VERSION 5.7 ;
  NOWIREEXTENSIONATPIN ON ;
  DIVIDERCHAR "/" ;
  BUSBITCHARS "[]" ;
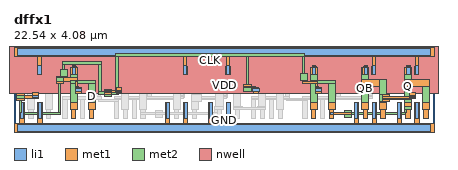
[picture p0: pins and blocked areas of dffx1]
MACRO dffx1
  CLASS BLOCK ;
  FOREIGN dffx1 ;
  ORIGIN 0.000 0.000 ;
  SIZE 22.540 BY 4.080 ;
  PIN CLK
    ANTENNAGATEAREA 1.323000 ;
    PORT
      LAYER li1 ;
        RECT 3.285 1.940 3.615 2.130 ;
        RECT 5.460 1.940 5.790 2.130 ;
        RECT 12.820 1.940 13.150 2.130 ;
        RECT 16.165 1.940 16.495 2.130 ;
        RECT 0.985 1.660 1.315 1.850 ;
      LAYER met1 ;
        RECT 2.470 2.780 2.850 3.130 ;
        RECT 2.260 2.730 2.850 2.780 ;
        RECT 2.260 2.520 3.430 2.730 ;
        RECT 15.350 2.540 15.730 2.920 ;
        RECT 2.260 2.400 2.640 2.520 ;
        RECT 3.290 2.240 3.430 2.520 ;
        RECT 15.470 2.520 15.730 2.540 ;
        RECT 15.470 2.380 16.310 2.520 ;
        RECT 12.340 2.240 12.720 2.360 ;
        RECT 16.170 2.240 16.310 2.380 ;
        RECT 3.290 2.200 3.440 2.240 ;
        RECT 12.340 2.200 12.950 2.240 ;
        RECT 16.170 2.200 16.320 2.240 ;
        RECT 3.290 2.100 3.600 2.200 ;
        RECT 0.160 1.750 0.540 1.870 ;
        RECT 1.000 1.750 1.300 1.920 ;
        RECT 3.300 1.870 3.600 2.100 ;
        RECT 4.850 2.030 5.230 2.080 ;
        RECT 5.475 2.030 5.775 2.200 ;
        RECT 4.850 1.890 5.775 2.030 ;
        RECT 12.340 1.980 13.135 2.200 ;
        RECT 16.170 2.100 16.480 2.200 ;
        RECT 0.160 1.610 1.300 1.750 ;
        RECT 4.850 1.700 5.230 1.890 ;
        RECT 5.475 1.870 5.775 1.890 ;
        RECT 12.835 1.870 13.135 1.980 ;
        RECT 16.180 1.870 16.480 2.100 ;
        RECT 0.160 1.490 0.540 1.610 ;
        RECT 1.000 1.600 1.300 1.610 ;
      LAYER met2 ;
        RECT 5.460 3.850 15.610 3.990 ;
        RECT 2.590 3.430 4.690 3.570 ;
        RECT 2.590 3.130 2.730 3.430 ;
        RECT 2.470 2.780 2.850 3.130 ;
        RECT 2.260 2.750 2.850 2.780 ;
        RECT 2.260 2.400 2.640 2.750 ;
        RECT 0.160 1.490 0.540 1.870 ;
        RECT 0.280 0.840 0.420 1.490 ;
        RECT 2.380 0.840 2.520 2.400 ;
        RECT 4.550 1.960 4.690 3.430 ;
        RECT 4.850 1.960 5.230 2.080 ;
        RECT 5.460 1.960 5.600 3.850 ;
        RECT 12.460 2.360 12.600 3.850 ;
        RECT 15.470 2.920 15.610 3.850 ;
        RECT 15.350 2.540 15.730 2.920 ;
        RECT 12.340 1.980 12.720 2.360 ;
        RECT 4.550 1.820 5.600 1.960 ;
        RECT 4.850 1.700 5.230 1.820 ;
        RECT 0.280 0.700 2.520 0.840 ;
    END
  END CLK
  PIN D
    ANTENNADIFFAREA 0.659400 ;
    PORT
      LAYER li1 ;
        RECT 3.145 2.870 3.315 3.330 ;
        RECT 3.125 0.490 3.295 1.370 ;
        RECT 4.085 0.490 4.255 1.370 ;
      LAYER met1 ;
        RECT 3.115 3.260 3.345 3.310 ;
        RECT 3.050 2.880 3.410 3.260 ;
        RECT 3.020 1.010 3.400 1.390 ;
        RECT 3.980 1.010 4.360 1.390 ;
        RECT 3.095 0.510 3.325 1.010 ;
        RECT 4.055 0.510 4.285 1.010 ;
      LAYER met2 ;
        RECT 3.040 2.560 3.420 3.260 ;
        RECT 3.020 2.400 4.360 2.560 ;
        RECT 3.020 1.010 3.400 2.400 ;
        RECT 3.980 1.010 4.360 2.400 ;
    END
  END D
  PIN QB
    ANTENNAGATEAREA 0.441000 ;
    ANTENNADIFFAREA 0.659400 ;
    PORT
      LAYER li1 ;
        RECT 18.785 2.870 18.955 3.330 ;
        RECT 21.225 1.660 21.555 1.850 ;
        RECT 18.765 0.490 18.935 1.370 ;
        RECT 19.725 0.490 19.895 1.370 ;
      LAYER met1 ;
        RECT 18.755 3.260 18.985 3.310 ;
        RECT 18.680 2.880 19.040 3.260 ;
        RECT 18.660 2.210 20.000 2.590 ;
        RECT 19.760 1.680 20.140 1.800 ;
        RECT 21.240 1.740 21.540 1.920 ;
        RECT 21.210 1.680 21.540 1.740 ;
        RECT 19.760 1.600 21.540 1.680 ;
        RECT 19.760 1.540 21.350 1.600 ;
        RECT 19.760 1.420 20.140 1.540 ;
        RECT 19.760 1.390 20.000 1.420 ;
        RECT 18.660 1.010 19.040 1.390 ;
        RECT 19.620 1.010 20.000 1.390 ;
        RECT 18.735 0.510 18.965 1.010 ;
        RECT 19.695 0.510 19.925 1.010 ;
      LAYER met2 ;
        RECT 18.660 1.010 19.050 3.260 ;
        RECT 19.620 1.800 20.000 2.590 ;
        RECT 19.620 1.420 20.140 1.800 ;
        RECT 19.620 1.010 20.000 1.420 ;
    END
  END QB
  PIN Q
    ANTENNADIFFAREA 1.318800 ;
    PORT
      LAYER li1 ;
        RECT 16.025 2.870 16.195 3.330 ;
        RECT 21.085 2.870 21.255 3.330 ;
        RECT 16.005 0.490 16.175 1.370 ;
        RECT 16.965 0.490 17.135 1.370 ;
        RECT 21.065 0.490 21.235 1.370 ;
        RECT 22.025 0.490 22.195 1.370 ;
      LAYER met1 ;
        RECT 15.995 3.260 16.225 3.310 ;
        RECT 21.055 3.260 21.285 3.310 ;
        RECT 15.930 2.880 16.290 3.260 ;
        RECT 20.980 2.880 21.340 3.260 ;
        RECT 20.960 2.210 22.300 2.590 ;
        RECT 15.900 1.010 16.280 1.390 ;
        RECT 16.860 1.010 17.240 1.390 ;
        RECT 20.960 1.010 21.340 1.390 ;
        RECT 21.920 1.010 22.300 1.390 ;
        RECT 15.975 0.510 16.205 1.010 ;
        RECT 16.935 0.840 17.165 1.010 ;
        RECT 17.730 0.840 18.110 0.960 ;
        RECT 16.935 0.700 18.110 0.840 ;
        RECT 16.935 0.510 17.165 0.700 ;
        RECT 17.730 0.580 18.110 0.700 ;
        RECT 21.035 0.510 21.265 1.010 ;
        RECT 21.995 0.510 22.225 1.010 ;
      LAYER met2 ;
        RECT 15.920 2.560 16.300 3.260 ;
        RECT 15.900 2.400 17.240 2.560 ;
        RECT 15.900 1.010 16.280 2.400 ;
        RECT 16.860 1.010 17.240 2.400 ;
        RECT 20.960 1.150 21.350 3.260 ;
        RECT 20.930 1.010 21.350 1.150 ;
        RECT 21.920 1.010 22.300 2.590 ;
        RECT 17.730 0.840 18.110 0.960 ;
        RECT 20.930 0.840 21.070 1.010 ;
        RECT 17.730 0.700 21.070 0.840 ;
        RECT 17.730 0.580 18.110 0.700 ;
    END
  END Q
  PIN VDD
    ANTENNADIFFAREA 7.041200 ;
    PORT
      LAYER nwell ;
        RECT -0.230 1.870 22.770 4.410 ;
      LAYER li1 ;
        RECT 0.210 3.915 22.330 4.245 ;
        RECT 1.285 2.870 1.455 3.330 ;
        RECT 9.105 2.870 9.275 3.330 ;
        RECT 11.405 2.870 11.575 3.330 ;
        RECT 19.225 2.870 19.395 3.330 ;
        RECT 21.525 2.870 21.695 3.330 ;
      LAYER met1 ;
        RECT 0.000 3.840 22.540 4.320 ;
        RECT 1.285 3.310 1.455 3.840 ;
        RECT 9.105 3.310 9.275 3.840 ;
        RECT 11.405 3.310 11.575 3.840 ;
        RECT 19.225 3.310 19.395 3.840 ;
        RECT 21.525 3.310 21.695 3.840 ;
        RECT 1.255 2.890 1.485 3.310 ;
        RECT 9.075 2.890 9.305 3.310 ;
        RECT 11.375 2.890 11.605 3.310 ;
        RECT 19.195 2.890 19.425 3.310 ;
        RECT 21.495 2.890 21.725 3.310 ;
    END
  END VDD
  PIN GND
    ANTENNADIFFAREA 9.120200 ;
    PORT
      LAYER li1 ;
        RECT 0.345 0.490 0.515 1.370 ;
        RECT 1.305 0.490 1.475 1.370 ;
        RECT 8.165 0.490 8.335 1.370 ;
        RECT 9.125 0.490 9.295 1.370 ;
        RECT 10.465 0.490 10.635 1.370 ;
        RECT 11.425 0.490 11.595 1.370 ;
        RECT 18.285 0.490 18.455 1.370 ;
        RECT 19.245 0.490 19.415 1.370 ;
        RECT 20.585 0.490 20.755 1.370 ;
        RECT 21.545 0.490 21.715 1.370 ;
        RECT 0.210 -0.165 22.330 0.165 ;
      LAYER met1 ;
        RECT 0.315 0.240 0.545 1.350 ;
        RECT 1.275 0.240 1.505 1.350 ;
        RECT 8.135 0.240 8.365 1.350 ;
        RECT 9.095 0.240 9.325 1.350 ;
        RECT 10.435 0.240 10.665 1.350 ;
        RECT 11.395 0.240 11.625 1.350 ;
        RECT 18.255 0.240 18.485 1.350 ;
        RECT 19.215 0.240 19.445 1.350 ;
        RECT 20.555 0.240 20.785 1.350 ;
        RECT 21.515 0.240 21.745 1.350 ;
        RECT 0.000 -0.240 22.540 0.240 ;
    END
  END GND
  OBS
      LAYER li1 ;
        RECT 0.845 2.870 1.015 3.330 ;
        RECT 3.585 2.870 3.755 3.330 ;
        RECT 5.905 2.870 6.075 3.330 ;
        RECT 6.345 2.870 6.515 3.330 ;
        RECT 8.665 2.870 8.835 3.330 ;
        RECT 10.965 2.870 11.135 3.330 ;
        RECT 13.265 2.870 13.435 3.330 ;
        RECT 13.705 2.870 13.875 3.330 ;
        RECT 16.465 2.870 16.635 3.330 ;
        RECT 2.700 1.940 3.030 2.130 ;
        RECT 6.045 1.940 6.375 2.130 ;
        RECT 13.405 1.940 13.735 2.130 ;
        RECT 15.580 1.940 15.910 2.130 ;
        RECT 8.805 1.660 9.135 1.850 ;
        RECT 11.105 1.660 11.435 1.850 ;
        RECT 18.925 1.660 19.255 1.850 ;
        RECT 0.825 0.490 0.995 1.370 ;
        RECT 1.785 0.490 1.955 1.370 ;
        RECT 2.645 0.490 2.815 1.370 ;
        RECT 3.605 0.490 3.775 1.370 ;
        RECT 5.405 0.490 5.575 1.370 ;
        RECT 5.885 0.490 6.055 1.370 ;
        RECT 6.365 0.490 6.535 1.370 ;
        RECT 6.845 0.490 7.015 1.370 ;
        RECT 8.645 0.490 8.815 1.370 ;
        RECT 9.605 0.490 9.775 1.370 ;
        RECT 10.945 0.490 11.115 1.370 ;
        RECT 11.905 0.490 12.075 1.370 ;
        RECT 12.765 0.490 12.935 1.370 ;
        RECT 13.245 0.490 13.415 1.370 ;
        RECT 13.725 0.490 13.895 1.370 ;
        RECT 14.205 0.490 14.375 1.370 ;
        RECT 15.525 0.490 15.695 1.370 ;
        RECT 16.485 0.490 16.655 1.370 ;
      LAYER met1 ;
        RECT 1.840 3.640 2.220 3.690 ;
        RECT 4.850 3.640 5.230 3.690 ;
        RECT 8.000 3.640 8.380 3.690 ;
        RECT 14.930 3.640 15.310 3.690 ;
        RECT 1.840 3.500 5.230 3.640 ;
        RECT 1.840 3.310 2.220 3.500 ;
        RECT 4.850 3.310 5.230 3.500 ;
        RECT 5.530 3.500 8.380 3.640 ;
        RECT 0.815 3.260 1.045 3.310 ;
        RECT 0.740 2.880 1.100 3.260 ;
        RECT 3.555 3.200 3.785 3.310 ;
        RECT 3.555 3.000 4.645 3.200 ;
        RECT 3.555 2.890 3.785 3.000 ;
        RECT 0.720 2.350 2.060 2.590 ;
        RECT 0.720 2.240 2.100 2.350 ;
        RECT 0.720 2.210 2.860 2.240 ;
        RECT 1.960 2.200 2.860 2.210 ;
        RECT 1.960 2.100 3.015 2.200 ;
        RECT 2.715 1.870 3.015 2.100 ;
        RECT 4.425 1.690 4.645 3.000 ;
        RECT 5.530 2.730 5.670 3.500 ;
        RECT 8.000 3.310 8.380 3.500 ;
        RECT 12.880 3.500 15.310 3.640 ;
        RECT 5.875 3.260 6.105 3.310 ;
        RECT 5.810 2.880 6.170 3.260 ;
        RECT 6.315 3.200 6.545 3.310 ;
        RECT 8.635 3.260 8.865 3.310 ;
        RECT 10.935 3.260 11.165 3.310 ;
        RECT 6.315 3.000 7.405 3.200 ;
        RECT 6.315 2.890 6.545 3.000 ;
        RECT 4.850 2.520 5.230 2.640 ;
        RECT 5.530 2.520 6.160 2.730 ;
        RECT 4.850 2.380 6.160 2.520 ;
        RECT 4.850 2.260 5.230 2.380 ;
        RECT 6.020 2.240 6.160 2.380 ;
        RECT 6.020 2.200 6.200 2.240 ;
        RECT 6.020 2.100 6.360 2.200 ;
        RECT 6.060 1.870 6.360 2.100 ;
        RECT 7.185 1.690 7.405 3.000 ;
        RECT 8.560 2.880 8.920 3.260 ;
        RECT 10.860 2.880 11.220 3.260 ;
        RECT 11.780 3.010 12.160 3.130 ;
        RECT 12.880 3.010 13.020 3.500 ;
        RECT 14.930 3.310 15.310 3.500 ;
        RECT 13.235 3.260 13.465 3.310 ;
        RECT 11.780 2.870 13.020 3.010 ;
        RECT 13.170 2.880 13.530 3.260 ;
        RECT 13.675 3.200 13.905 3.310 ;
        RECT 16.435 3.200 16.665 3.310 ;
        RECT 13.675 3.000 14.765 3.200 ;
        RECT 13.675 2.890 13.905 3.000 ;
        RECT 11.780 2.750 12.160 2.870 ;
        RECT 12.880 2.730 13.020 2.870 ;
        RECT 8.540 2.210 9.880 2.590 ;
        RECT 10.840 2.210 12.180 2.590 ;
        RECT 12.880 2.380 13.510 2.730 ;
        RECT 13.370 2.240 13.510 2.380 ;
        RECT 13.370 2.200 13.560 2.240 ;
        RECT 13.370 2.100 13.720 2.200 ;
        RECT 8.820 1.740 9.120 1.920 ;
        RECT 2.615 1.680 4.645 1.690 ;
        RECT 5.375 1.680 7.405 1.690 ;
        RECT 8.750 1.680 9.120 1.740 ;
        RECT 2.615 1.540 4.690 1.680 ;
        RECT 5.375 1.600 9.120 1.680 ;
        RECT 9.680 1.680 10.060 1.800 ;
        RECT 11.120 1.740 11.420 1.920 ;
        RECT 13.420 1.870 13.720 2.100 ;
        RECT 11.060 1.680 11.420 1.740 ;
        RECT 14.545 1.690 14.765 3.000 ;
        RECT 16.435 3.000 17.525 3.200 ;
        RECT 16.435 2.890 16.665 3.000 ;
        RECT 14.930 2.240 15.310 2.360 ;
        RECT 14.930 2.200 15.740 2.240 ;
        RECT 14.930 2.100 15.895 2.200 ;
        RECT 14.930 1.980 15.310 2.100 ;
        RECT 15.595 1.870 15.895 2.100 ;
        RECT 17.305 1.690 17.525 3.000 ;
        RECT 18.940 1.740 19.240 1.920 ;
        RECT 9.680 1.600 11.420 1.680 ;
        RECT 12.735 1.610 14.765 1.690 ;
        RECT 15.495 1.680 17.525 1.690 ;
        RECT 18.900 1.680 19.240 1.740 ;
        RECT 15.495 1.610 19.240 1.680 ;
        RECT 12.735 1.600 19.240 1.610 ;
        RECT 5.375 1.540 8.890 1.600 ;
        RECT 9.680 1.540 11.200 1.600 ;
        RECT 12.735 1.540 19.040 1.600 ;
        RECT 0.720 1.010 1.100 1.390 ;
        RECT 1.680 1.010 2.060 1.390 ;
        RECT 0.795 0.510 1.025 1.010 ;
        RECT 1.755 0.510 1.985 1.010 ;
        RECT 2.615 0.510 2.845 1.540 ;
        RECT 3.575 0.510 3.805 1.540 ;
        RECT 4.550 1.400 5.605 1.540 ;
        RECT 5.375 0.510 5.605 1.400 ;
        RECT 5.780 1.010 6.160 1.390 ;
        RECT 5.855 0.510 6.085 1.010 ;
        RECT 6.335 0.510 6.565 1.540 ;
        RECT 9.680 1.420 10.060 1.540 ;
        RECT 9.680 1.390 9.880 1.420 ;
        RECT 6.740 1.010 7.120 1.390 ;
        RECT 8.540 1.010 8.920 1.390 ;
        RECT 9.500 1.010 9.880 1.390 ;
        RECT 10.840 1.010 11.220 1.390 ;
        RECT 11.800 1.010 12.180 1.390 ;
        RECT 6.815 0.840 7.045 1.010 ;
        RECT 7.580 0.840 7.960 0.960 ;
        RECT 6.815 0.700 7.960 0.840 ;
        RECT 6.815 0.510 7.045 0.700 ;
        RECT 7.580 0.580 7.960 0.700 ;
        RECT 8.615 0.510 8.845 1.010 ;
        RECT 9.575 0.510 9.805 1.010 ;
        RECT 10.915 0.510 11.145 1.010 ;
        RECT 11.875 0.510 12.105 1.010 ;
        RECT 12.735 0.510 12.965 1.540 ;
        RECT 13.140 1.010 13.520 1.390 ;
        RECT 13.215 0.510 13.445 1.010 ;
        RECT 13.695 0.510 13.925 1.540 ;
        RECT 14.630 1.470 15.725 1.540 ;
        RECT 14.100 1.010 14.480 1.390 ;
        RECT 14.175 0.510 14.405 1.010 ;
        RECT 15.495 0.510 15.725 1.470 ;
        RECT 16.455 0.510 16.685 1.540 ;
      LAYER met2 ;
        RECT 1.840 3.310 2.220 3.690 ;
        RECT 4.850 3.310 5.230 3.690 ;
        RECT 8.000 3.570 8.380 3.690 ;
        RECT 8.000 3.430 12.040 3.570 ;
        RECT 8.000 3.310 8.380 3.430 ;
        RECT 0.720 1.010 1.110 3.260 ;
        RECT 1.960 2.660 2.100 3.310 ;
        RECT 1.920 2.590 2.100 2.660 ;
        RECT 4.970 2.640 5.110 3.310 ;
        RECT 1.680 2.520 2.100 2.590 ;
        RECT 1.680 1.010 2.060 2.520 ;
        RECT 4.850 2.260 5.230 2.640 ;
        RECT 5.800 2.560 6.180 3.260 ;
        RECT 5.780 2.400 7.120 2.560 ;
        RECT 5.780 1.010 6.160 2.400 ;
        RECT 6.740 1.010 7.120 2.400 ;
        RECT 8.540 1.010 8.930 3.260 ;
        RECT 9.500 1.800 9.880 2.590 ;
        RECT 9.500 1.420 10.060 1.800 ;
        RECT 9.500 1.010 9.880 1.420 ;
        RECT 10.840 1.150 11.230 3.260 ;
        RECT 11.900 3.130 12.040 3.430 ;
        RECT 14.930 3.310 15.310 3.690 ;
        RECT 11.780 2.750 12.160 3.130 ;
        RECT 10.780 1.010 11.230 1.150 ;
        RECT 11.800 1.150 12.180 2.590 ;
        RECT 13.160 2.560 13.540 3.260 ;
        RECT 13.140 2.400 14.480 2.560 ;
        RECT 13.140 1.150 13.520 2.400 ;
        RECT 11.800 1.120 12.250 1.150 ;
        RECT 13.090 1.120 13.520 1.150 ;
        RECT 11.800 1.010 13.520 1.120 ;
        RECT 14.100 1.010 14.480 2.400 ;
        RECT 15.050 2.360 15.190 3.310 ;
        RECT 14.930 1.980 15.310 2.360 ;
        RECT 7.580 0.840 7.960 0.960 ;
        RECT 10.780 0.840 10.920 1.010 ;
        RECT 12.110 0.980 13.230 1.010 ;
        RECT 7.580 0.700 10.920 0.840 ;
        RECT 7.580 0.580 7.960 0.700 ;
  END
END dffx1
END LIBRARY

